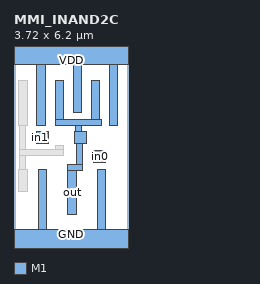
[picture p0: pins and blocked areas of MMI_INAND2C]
MACRO MMI_INAND2C
	CLASS CORE ;
	FOREIGN MMI_INAND2C 0 0 ;
	SIZE 3.72 BY 6.2 ;
	SYMMETRY X Y ;
	SITE CORE1 ;
	PIN out
		DIRECTION output ;
		USE SIGNAL ;
		PORT
			LAYER M1 ;
			RECT 1.34 3.995 1.62 5.27 ;
			LAYER M1 ;
			RECT 2.52 3.995 2.8 5.27 ;
			LAYER M1 ;
			RECT 1.34 3.8 2.85 3.995 ;
			LAYER M1 ;
			RECT 2.015 3.6 2.21 3.8 ;
			LAYER M1 ;
			RECT 1.98 3.22 2.36 3.6 ;
			LAYER M1 ;
			RECT 2.03 2.52 2.225 3.22 ;
			LAYER M1 ;
			RECT 1.76 2.33 2.225 2.52 ;
			LAYER M1 ;
			RECT 1.76 0.885 2.04 2.33 ;
		END
		AntennaDiffArea 2.0328 ;
	END out
	PIN in1
		DIRECTION input ;
		USE SIGNAL ;
		PORT
			LAYER M1 ;
			RECT 0.74 3.55 1.12 3.6 ;
			LAYER M1 ;
			RECT 0.575 3.27 1.12 3.55 ;
			LAYER M1 ;
			RECT 0.74 3.22 1.12 3.27 ;
		END
		AntennaGateArea 0.3465 ;
	END in1
	PIN GND
		DIRECTION inout ;
		USE GROUND ;
		PORT
			LAYER M1 ;
			RECT 0.795 0.42 1.075 2.355 ;
			LAYER M1 ;
			RECT 2.72 0.42 3 2.355 ;
			LAYER M1 ;
			RECT 0 -0.42 3.72 0.42 ;
		END
	END GND
	PIN VDD
		DIRECTION inout ;
		USE POWER ;
		PORT
			LAYER M1 ;
			RECT 0 5.78 3.72 6.62 ;
			LAYER M1 ;
			RECT 0.75 3.8 1.03 5.78 ;
			LAYER M1 ;
			RECT 1.93 4.21 2.21 5.78 ;
			LAYER M1 ;
			RECT 3.11 3.8 3.39 5.78 ;
		END
	END VDD
	PIN in0
		DIRECTION input ;
		USE SIGNAL ;
		PORT
			LAYER M1 ;
			RECT 2.6 2.6 2.98 2.98 ;
		END
		AntennaGateArea 0.924 ;
	END in0
	OBS
		LAYER M1 ;
		RECT 0.16 3.8 0.44 5.27 ;
		LAYER M1 ;
		RECT 0.185 3.015 0.375 3.8 ;
		LAYER M1 ;
		RECT 1.345 3.015 1.625 3.145 ;
		LAYER M1 ;
		RECT 0.185 2.825 1.625 3.015 ;
		LAYER M1 ;
		RECT 0.185 2.355 0.375 2.825 ;
		LAYER M1 ;
		RECT 0.16 1.655 0.44 2.355 ;
	END
END MMI_INAND2C
